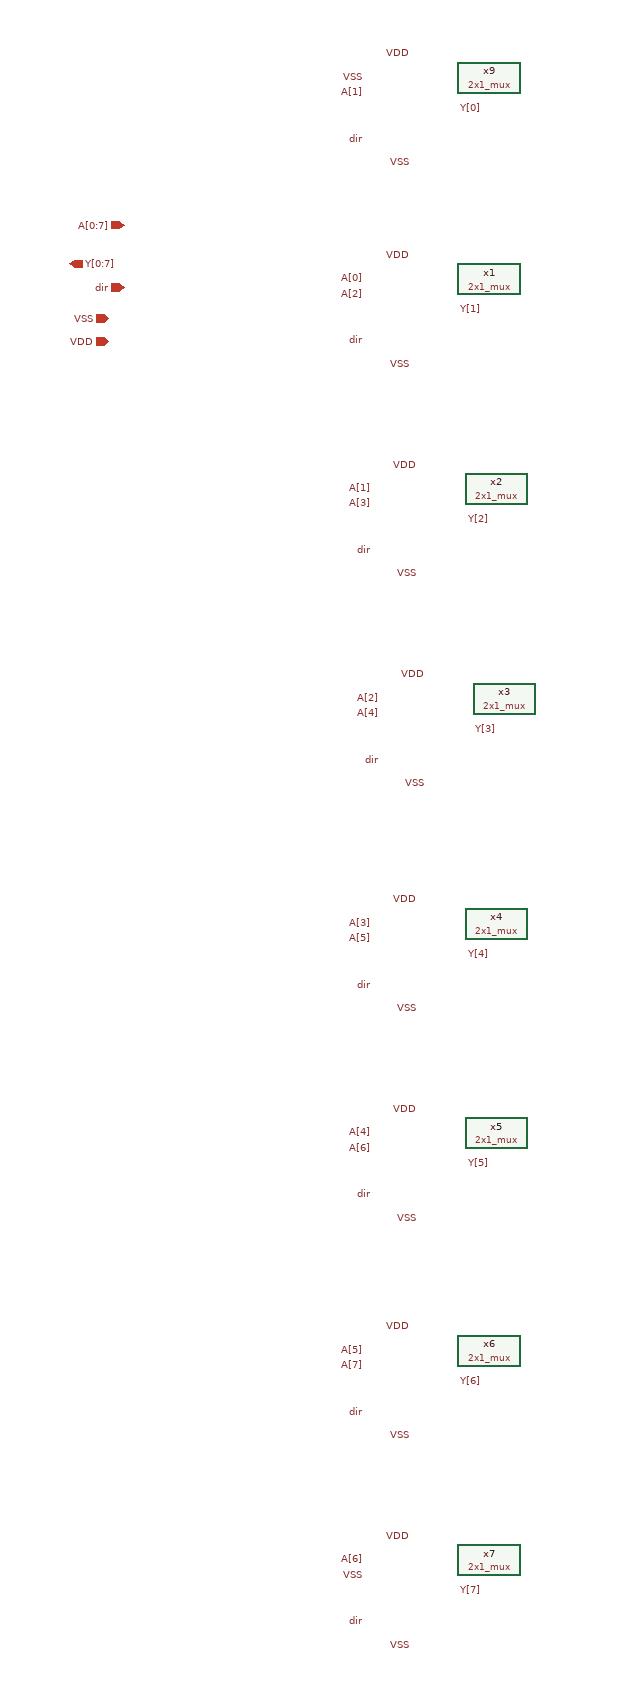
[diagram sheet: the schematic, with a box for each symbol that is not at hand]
v {xschem version=3.1.0 file_version=1.2 }
G {}
K {}
V {}
S {}
E {}
C {devices/ipin.sym} -130 -190 0 0 {name=p3 lab=A[0:7]}
C {devices/opin.sym} -200 -140 0 0 {name=p9 lab=Y[0:7]}
C {devices/ipin.sym} -130 -110 0 0 {name=p1 lab=dir}
C {devices/lab_pin.sym} 300 -340 2 0 {name=l27 sig_type=std_logic lab=Y[0]}
C {devices/lab_pin.sym} 180 -300 0 0 {name=l36 sig_type=std_logic lab=dir}
C {devices/lab_pin.sym} 240 -410 1 0 {name=l75 sig_type=std_logic lab=VDD}
C {devices/lab_pin.sym} 240 -270 3 0 {name=l101 sig_type=std_logic lab=VSS}
C {2x1_mux.sym} 340 -380 0 0 {name=x9}
C {devices/lab_pin.sym} 180 -360 0 0 {name=l1 sig_type=std_logic lab=A[1]}
C {devices/lab_pin.sym} 300 -80 2 0 {name=l2 sig_type=std_logic lab=Y[1]}
C {devices/lab_pin.sym} 180 -40 0 0 {name=l3 sig_type=std_logic lab=dir}
C {devices/lab_pin.sym} 180 -120 0 0 {name=l4 sig_type=std_logic lab=A[0]}
C {devices/lab_pin.sym} 240 -150 1 0 {name=l5 sig_type=std_logic lab=VDD}
C {devices/lab_pin.sym} 240 -10 3 0 {name=l6 sig_type=std_logic lab=VSS}
C {2x1_mux.sym} 340 -120 0 0 {name=x1}
C {devices/lab_pin.sym} 180 -100 0 0 {name=l7 sig_type=std_logic lab=A[2]}
C {devices/lab_pin.sym} 310 190 2 0 {name=l8 sig_type=std_logic lab=Y[2]}
C {devices/lab_pin.sym} 190 230 0 0 {name=l9 sig_type=std_logic lab=dir}
C {devices/lab_pin.sym} 190 150 0 0 {name=l10 sig_type=std_logic lab=A[1]}
C {devices/lab_pin.sym} 250 120 1 0 {name=l11 sig_type=std_logic lab=VDD}
C {devices/lab_pin.sym} 250 260 3 0 {name=l12 sig_type=std_logic lab=VSS}
C {2x1_mux.sym} 350 150 0 0 {name=x2}
C {devices/lab_pin.sym} 190 170 0 0 {name=l13 sig_type=std_logic lab=A[3]}
C {devices/lab_pin.sym} 320 460 2 0 {name=l14 sig_type=std_logic lab=Y[3]}
C {devices/lab_pin.sym} 200 500 0 0 {name=l15 sig_type=std_logic lab=dir}
C {devices/lab_pin.sym} 200 420 0 0 {name=l16 sig_type=std_logic lab=A[2]}
C {devices/lab_pin.sym} 260 390 1 0 {name=l17 sig_type=std_logic lab=VDD}
C {devices/lab_pin.sym} 260 530 3 0 {name=l18 sig_type=std_logic lab=VSS}
C {2x1_mux.sym} 360 420 0 0 {name=x3}
C {devices/lab_pin.sym} 310 750 2 0 {name=l20 sig_type=std_logic lab=Y[4]}
C {devices/lab_pin.sym} 190 790 0 0 {name=l21 sig_type=std_logic lab=dir}
C {devices/lab_pin.sym} 190 710 0 0 {name=l22 sig_type=std_logic lab=A[3]}
C {devices/lab_pin.sym} 250 680 1 0 {name=l23 sig_type=std_logic lab=VDD}
C {devices/lab_pin.sym} 250 820 3 0 {name=l24 sig_type=std_logic lab=VSS}
C {2x1_mux.sym} 350 710 0 0 {name=x4}
C {devices/lab_pin.sym} 310 1020 2 0 {name=l26 sig_type=std_logic lab=Y[5]}
C {devices/lab_pin.sym} 190 1060 0 0 {name=l28 sig_type=std_logic lab=dir}
C {devices/lab_pin.sym} 190 980 0 0 {name=l29 sig_type=std_logic lab=A[4]}
C {devices/lab_pin.sym} 250 950 1 0 {name=l30 sig_type=std_logic lab=VDD}
C {devices/lab_pin.sym} 250 1090 3 0 {name=l31 sig_type=std_logic lab=VSS}
C {2x1_mux.sym} 350 980 0 0 {name=x5}
C {devices/lab_pin.sym} 300 1300 2 0 {name=l33 sig_type=std_logic lab=Y[6]}
C {devices/lab_pin.sym} 180 1340 0 0 {name=l34 sig_type=std_logic lab=dir}
C {devices/lab_pin.sym} 180 1260 0 0 {name=l35 sig_type=std_logic lab=A[5]}
C {devices/lab_pin.sym} 240 1230 1 0 {name=l37 sig_type=std_logic lab=VDD}
C {devices/lab_pin.sym} 240 1370 3 0 {name=l38 sig_type=std_logic lab=VSS}
C {2x1_mux.sym} 340 1260 0 0 {name=x6}
C {devices/lab_pin.sym} 300 1570 2 0 {name=l40 sig_type=std_logic lab=Y[7]}
C {devices/lab_pin.sym} 180 1610 0 0 {name=l41 sig_type=std_logic lab=dir}
C {devices/lab_pin.sym} 180 1530 0 0 {name=l42 sig_type=std_logic lab=A[6]}
C {devices/lab_pin.sym} 240 1500 1 0 {name=l43 sig_type=std_logic lab=VDD}
C {devices/lab_pin.sym} 240 1640 3 0 {name=l44 sig_type=std_logic lab=VSS}
C {2x1_mux.sym} 340 1530 0 0 {name=x7}
C {devices/lab_pin.sym} 200 440 0 0 {name=l19 sig_type=std_logic lab=A[4]}
C {devices/lab_pin.sym} 190 730 0 0 {name=l25 sig_type=std_logic lab=A[5]}
C {devices/lab_pin.sym} 190 1000 0 0 {name=l32 sig_type=std_logic lab=A[6]}
C {devices/lab_pin.sym} 180 1280 0 0 {name=l39 sig_type=std_logic lab=A[7]}
C {devices/iopin.sym} -150 -70 2 0 {name=p6 lab=VSS}
C {devices/iopin.sym} -150 -40 2 0 {name=p7 lab=VDD}
C {devices/lab_pin.sym} 180 -380 0 0 {name=l46 sig_type=std_logic lab=VSS}
C {devices/lab_pin.sym} 180 1550 0 0 {name=l47 sig_type=std_logic lab=VSS}
